VERSION 5.7 ;
  NOWIREEXTENSIONATPIN ON ;
  DIVIDERCHAR "/" ;
  BUSBITCHARS "[]" ;
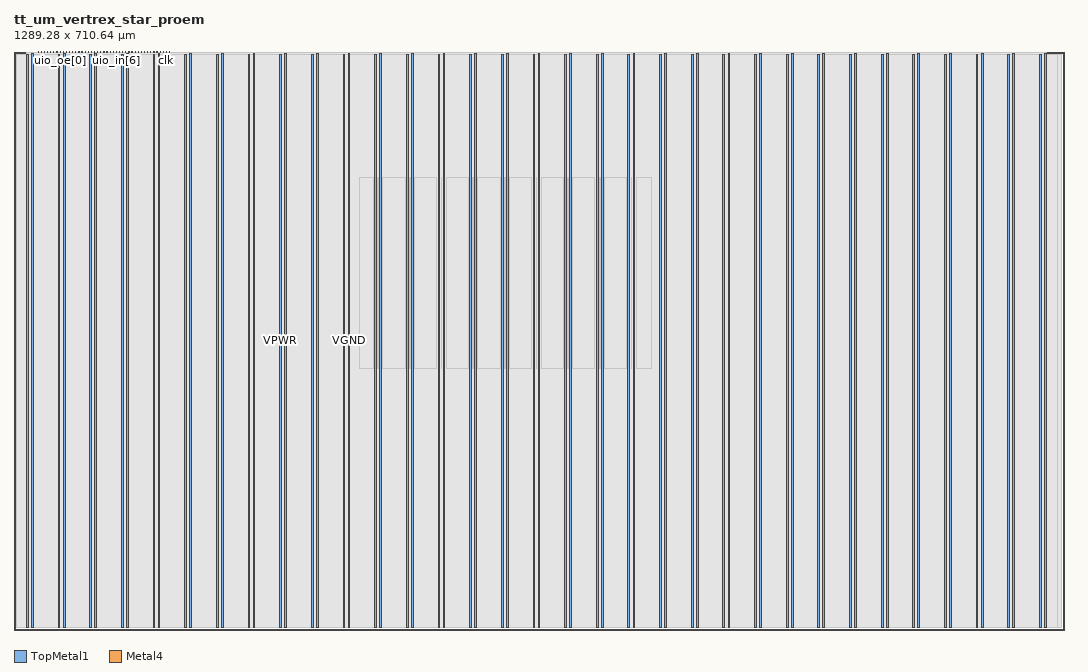
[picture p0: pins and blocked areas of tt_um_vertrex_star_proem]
MACRO tt_um_vertrex_star_proem
  CLASS BLOCK ;
  FOREIGN tt_um_vertrex_star_proem ;
  ORIGIN 0.000 0.000 ;
  SIZE 1289.280 BY 710.640 ;
  PIN VGND
    DIRECTION INOUT ;
    USE GROUND ;
    PORT
      LAYER TopMetal1 ;
        RECT 21.580 3.150 23.780 707.490 ;
    END
    PORT
      LAYER TopMetal1 ;
        RECT 60.450 3.150 62.650 707.490 ;
    END
    PORT
      LAYER TopMetal1 ;
        RECT 99.320 3.150 101.520 707.490 ;
    END
    PORT
      LAYER TopMetal1 ;
        RECT 138.190 3.150 140.390 707.490 ;
    END
    PORT
      LAYER TopMetal1 ;
        RECT 177.060 3.150 179.260 707.490 ;
    END
    PORT
      LAYER TopMetal1 ;
        RECT 215.930 3.150 218.130 707.490 ;
    END
    PORT
      LAYER TopMetal1 ;
        RECT 254.800 3.150 257.000 707.490 ;
    END
    PORT
      LAYER TopMetal1 ;
        RECT 293.670 3.150 295.870 707.490 ;
    END
    PORT
      LAYER TopMetal1 ;
        RECT 332.540 3.150 334.740 707.490 ;
    END
    PORT
      LAYER TopMetal1 ;
        RECT 371.410 3.150 373.610 707.490 ;
    END
    PORT
      LAYER TopMetal1 ;
        RECT 410.280 3.150 412.480 707.490 ;
    END
    PORT
      LAYER TopMetal1 ;
        RECT 449.150 3.150 451.350 707.490 ;
    END
    PORT
      LAYER TopMetal1 ;
        RECT 488.020 3.150 490.220 707.490 ;
    END
    PORT
      LAYER TopMetal1 ;
        RECT 526.890 3.150 529.090 707.490 ;
    END
    PORT
      LAYER TopMetal1 ;
        RECT 565.760 3.150 567.960 707.490 ;
    END
    PORT
      LAYER TopMetal1 ;
        RECT 604.630 3.150 606.830 707.490 ;
    END
    PORT
      LAYER TopMetal1 ;
        RECT 643.500 3.150 645.700 707.490 ;
    END
    PORT
      LAYER TopMetal1 ;
        RECT 682.370 3.150 684.570 707.490 ;
    END
    PORT
      LAYER TopMetal1 ;
        RECT 721.240 3.150 723.440 707.490 ;
    END
    PORT
      LAYER TopMetal1 ;
        RECT 760.110 3.150 762.310 707.490 ;
    END
    PORT
      LAYER TopMetal1 ;
        RECT 798.980 3.150 801.180 707.490 ;
    END
    PORT
      LAYER TopMetal1 ;
        RECT 837.850 3.150 840.050 707.490 ;
    END
    PORT
      LAYER TopMetal1 ;
        RECT 876.720 3.150 878.920 707.490 ;
    END
    PORT
      LAYER TopMetal1 ;
        RECT 915.590 3.150 917.790 707.490 ;
    END
    PORT
      LAYER TopMetal1 ;
        RECT 954.460 3.150 956.660 707.490 ;
    END
    PORT
      LAYER TopMetal1 ;
        RECT 993.330 3.150 995.530 707.490 ;
    END
    PORT
      LAYER TopMetal1 ;
        RECT 1032.200 3.150 1034.400 707.490 ;
    END
    PORT
      LAYER TopMetal1 ;
        RECT 1071.070 3.150 1073.270 707.490 ;
    END
    PORT
      LAYER TopMetal1 ;
        RECT 1109.940 3.150 1112.140 707.490 ;
    END
    PORT
      LAYER TopMetal1 ;
        RECT 1148.810 3.150 1151.010 707.490 ;
    END
    PORT
      LAYER TopMetal1 ;
        RECT 1187.680 3.150 1189.880 707.490 ;
    END
    PORT
      LAYER TopMetal1 ;
        RECT 1226.550 3.150 1228.750 707.490 ;
    END
    PORT
      LAYER TopMetal1 ;
        RECT 1265.420 3.150 1267.620 707.490 ;
    END
  END VGND
  PIN VPWR
    DIRECTION INOUT ;
    USE POWER ;
    PORT
      LAYER TopMetal1 ;
        RECT 15.380 3.560 17.580 707.080 ;
    END
    PORT
      LAYER TopMetal1 ;
        RECT 54.250 3.560 56.450 707.080 ;
    END
    PORT
      LAYER TopMetal1 ;
        RECT 93.120 3.560 95.320 707.080 ;
    END
    PORT
      LAYER TopMetal1 ;
        RECT 131.990 3.560 134.190 707.080 ;
    END
    PORT
      LAYER TopMetal1 ;
        RECT 170.860 3.560 173.060 707.080 ;
    END
    PORT
      LAYER TopMetal1 ;
        RECT 209.730 3.560 211.930 707.080 ;
    END
    PORT
      LAYER TopMetal1 ;
        RECT 248.600 3.560 250.800 707.080 ;
    END
    PORT
      LAYER TopMetal1 ;
        RECT 287.470 3.560 289.670 707.080 ;
    END
    PORT
      LAYER TopMetal1 ;
        RECT 326.340 3.560 328.540 707.080 ;
    END
    PORT
      LAYER TopMetal1 ;
        RECT 365.210 3.560 367.410 707.080 ;
    END
    PORT
      LAYER TopMetal1 ;
        RECT 404.080 3.560 406.280 707.080 ;
    END
    PORT
      LAYER TopMetal1 ;
        RECT 442.950 3.560 445.150 707.080 ;
    END
    PORT
      LAYER TopMetal1 ;
        RECT 481.820 3.560 484.020 707.080 ;
    END
    PORT
      LAYER TopMetal1 ;
        RECT 520.690 3.560 522.890 707.080 ;
    END
    PORT
      LAYER TopMetal1 ;
        RECT 559.560 3.560 561.760 707.080 ;
    END
    PORT
      LAYER TopMetal1 ;
        RECT 598.430 3.560 600.630 707.080 ;
    END
    PORT
      LAYER TopMetal1 ;
        RECT 637.300 3.560 639.500 707.080 ;
    END
    PORT
      LAYER TopMetal1 ;
        RECT 676.170 3.560 678.370 707.080 ;
    END
    PORT
      LAYER TopMetal1 ;
        RECT 715.040 3.560 717.240 707.080 ;
    END
    PORT
      LAYER TopMetal1 ;
        RECT 753.910 3.560 756.110 707.080 ;
    END
    PORT
      LAYER TopMetal1 ;
        RECT 792.780 3.560 794.980 707.080 ;
    END
    PORT
      LAYER TopMetal1 ;
        RECT 831.650 3.560 833.850 707.080 ;
    END
    PORT
      LAYER TopMetal1 ;
        RECT 870.520 3.560 872.720 707.080 ;
    END
    PORT
      LAYER TopMetal1 ;
        RECT 909.390 3.560 911.590 707.080 ;
    END
    PORT
      LAYER TopMetal1 ;
        RECT 948.260 3.560 950.460 707.080 ;
    END
    PORT
      LAYER TopMetal1 ;
        RECT 987.130 3.560 989.330 707.080 ;
    END
    PORT
      LAYER TopMetal1 ;
        RECT 1026.000 3.560 1028.200 707.080 ;
    END
    PORT
      LAYER TopMetal1 ;
        RECT 1064.870 3.560 1067.070 707.080 ;
    END
    PORT
      LAYER TopMetal1 ;
        RECT 1103.740 3.560 1105.940 707.080 ;
    END
    PORT
      LAYER TopMetal1 ;
        RECT 1142.610 3.560 1144.810 707.080 ;
    END
    PORT
      LAYER TopMetal1 ;
        RECT 1181.480 3.560 1183.680 707.080 ;
    END
    PORT
      LAYER TopMetal1 ;
        RECT 1220.350 3.560 1222.550 707.080 ;
    END
    PORT
      LAYER TopMetal1 ;
        RECT 1259.220 3.560 1261.420 707.080 ;
    END
  END VPWR
  PIN clk
    DIRECTION INPUT ;
    USE SIGNAL ;
    ANTENNAGATEAREA 1.450800 ;
    PORT
      LAYER Metal4 ;
        RECT 187.050 709.640 187.350 710.640 ;
    END
  END clk
  PIN ena
    DIRECTION INPUT ;
    USE SIGNAL ;
    PORT
      LAYER Metal4 ;
        RECT 190.890 709.640 191.190 710.640 ;
    END
  END ena
  PIN rst_n
    DIRECTION INPUT ;
    USE SIGNAL ;
    ANTENNAGATEAREA 0.180700 ;
    PORT
      LAYER Metal4 ;
        RECT 183.210 709.640 183.510 710.640 ;
    END
  END rst_n
  PIN ui_in[0]
    DIRECTION INPUT ;
    USE SIGNAL ;
    ANTENNAGATEAREA 0.180700 ;
    PORT
      LAYER Metal4 ;
        RECT 179.370 709.640 179.670 710.640 ;
    END
  END ui_in[0]
  PIN ui_in[1]
    DIRECTION INPUT ;
    USE SIGNAL ;
    PORT
      LAYER Metal4 ;
        RECT 175.530 709.640 175.830 710.640 ;
    END
  END ui_in[1]
  PIN ui_in[2]
    DIRECTION INPUT ;
    USE SIGNAL ;
    PORT
      LAYER Metal4 ;
        RECT 171.690 709.640 171.990 710.640 ;
    END
  END ui_in[2]
  PIN ui_in[3]
    DIRECTION INPUT ;
    USE SIGNAL ;
    PORT
      LAYER Metal4 ;
        RECT 167.850 709.640 168.150 710.640 ;
    END
  END ui_in[3]
  PIN ui_in[4]
    DIRECTION INPUT ;
    USE SIGNAL ;
    PORT
      LAYER Metal4 ;
        RECT 164.010 709.640 164.310 710.640 ;
    END
  END ui_in[4]
  PIN ui_in[5]
    DIRECTION INPUT ;
    USE SIGNAL ;
    PORT
      LAYER Metal4 ;
        RECT 160.170 709.640 160.470 710.640 ;
    END
  END ui_in[5]
  PIN ui_in[6]
    DIRECTION INPUT ;
    USE SIGNAL ;
    PORT
      LAYER Metal4 ;
        RECT 156.330 709.640 156.630 710.640 ;
    END
  END ui_in[6]
  PIN ui_in[7]
    DIRECTION INPUT ;
    USE SIGNAL ;
    PORT
      LAYER Metal4 ;
        RECT 152.490 709.640 152.790 710.640 ;
    END
  END ui_in[7]
  PIN uio_in[0]
    DIRECTION INPUT ;
    USE SIGNAL ;
    ANTENNAGATEAREA 0.180700 ;
    PORT
      LAYER Metal4 ;
        RECT 148.650 709.640 148.950 710.640 ;
    END
  END uio_in[0]
  PIN uio_in[1]
    DIRECTION INPUT ;
    USE SIGNAL ;
    ANTENNAGATEAREA 0.180700 ;
    PORT
      LAYER Metal4 ;
        RECT 144.810 709.640 145.110 710.640 ;
    END
  END uio_in[1]
  PIN uio_in[2]
    DIRECTION INPUT ;
    USE SIGNAL ;
    ANTENNAGATEAREA 0.180700 ;
    PORT
      LAYER Metal4 ;
        RECT 140.970 709.640 141.270 710.640 ;
    END
  END uio_in[2]
  PIN uio_in[3]
    DIRECTION INPUT ;
    USE SIGNAL ;
    ANTENNAGATEAREA 0.180700 ;
    PORT
      LAYER Metal4 ;
        RECT 137.130 709.640 137.430 710.640 ;
    END
  END uio_in[3]
  PIN uio_in[4]
    DIRECTION INPUT ;
    USE SIGNAL ;
    ANTENNAGATEAREA 0.180700 ;
    PORT
      LAYER Metal4 ;
        RECT 133.290 709.640 133.590 710.640 ;
    END
  END uio_in[4]
  PIN uio_in[5]
    DIRECTION INPUT ;
    USE SIGNAL ;
    ANTENNAGATEAREA 0.180700 ;
    PORT
      LAYER Metal4 ;
        RECT 129.450 709.640 129.750 710.640 ;
    END
  END uio_in[5]
  PIN uio_in[6]
    DIRECTION INPUT ;
    USE SIGNAL ;
    ANTENNAGATEAREA 0.180700 ;
    PORT
      LAYER Metal4 ;
        RECT 125.610 709.640 125.910 710.640 ;
    END
  END uio_in[6]
  PIN uio_in[7]
    DIRECTION INPUT ;
    USE SIGNAL ;
    ANTENNAGATEAREA 0.180700 ;
    PORT
      LAYER Metal4 ;
        RECT 121.770 709.640 122.070 710.640 ;
    END
  END uio_in[7]
  PIN uio_oe[0]
    DIRECTION OUTPUT ;
    USE SIGNAL ;
    ANTENNADIFFAREA 0.708600 ;
    PORT
      LAYER Metal4 ;
        RECT 56.490 709.640 56.790 710.640 ;
    END
  END uio_oe[0]
  PIN uio_oe[1]
    DIRECTION OUTPUT ;
    USE SIGNAL ;
    ANTENNADIFFAREA 0.708600 ;
    PORT
      LAYER Metal4 ;
        RECT 52.650 709.640 52.950 710.640 ;
    END
  END uio_oe[1]
  PIN uio_oe[2]
    DIRECTION OUTPUT ;
    USE SIGNAL ;
    ANTENNADIFFAREA 0.708600 ;
    PORT
      LAYER Metal4 ;
        RECT 48.810 709.640 49.110 710.640 ;
    END
  END uio_oe[2]
  PIN uio_oe[3]
    DIRECTION OUTPUT ;
    USE SIGNAL ;
    ANTENNADIFFAREA 0.708600 ;
    PORT
      LAYER Metal4 ;
        RECT 44.970 709.640 45.270 710.640 ;
    END
  END uio_oe[3]
  PIN uio_oe[4]
    DIRECTION OUTPUT ;
    USE SIGNAL ;
    ANTENNADIFFAREA 0.708600 ;
    PORT
      LAYER Metal4 ;
        RECT 41.130 709.640 41.430 710.640 ;
    END
  END uio_oe[4]
  PIN uio_oe[5]
    DIRECTION OUTPUT ;
    USE SIGNAL ;
    ANTENNADIFFAREA 0.708600 ;
    PORT
      LAYER Metal4 ;
        RECT 37.290 709.640 37.590 710.640 ;
    END
  END uio_oe[5]
  PIN uio_oe[6]
    DIRECTION OUTPUT ;
    USE SIGNAL ;
    ANTENNADIFFAREA 0.299200 ;
    PORT
      LAYER Metal4 ;
        RECT 33.450 709.640 33.750 710.640 ;
    END
  END uio_oe[6]
  PIN uio_oe[7]
    DIRECTION OUTPUT ;
    USE SIGNAL ;
    ANTENNADIFFAREA 0.299200 ;
    PORT
      LAYER Metal4 ;
        RECT 29.610 709.640 29.910 710.640 ;
    END
  END uio_oe[7]
  PIN uio_out[0]
    DIRECTION OUTPUT ;
    USE SIGNAL ;
    ANTENNADIFFAREA 0.708600 ;
    PORT
      LAYER Metal4 ;
        RECT 87.210 709.640 87.510 710.640 ;
    END
  END uio_out[0]
  PIN uio_out[1]
    DIRECTION OUTPUT ;
    USE SIGNAL ;
    ANTENNADIFFAREA 0.708600 ;
    PORT
      LAYER Metal4 ;
        RECT 83.370 709.640 83.670 710.640 ;
    END
  END uio_out[1]
  PIN uio_out[2]
    DIRECTION OUTPUT ;
    USE SIGNAL ;
    ANTENNADIFFAREA 0.708600 ;
    PORT
      LAYER Metal4 ;
        RECT 79.530 709.640 79.830 710.640 ;
    END
  END uio_out[2]
  PIN uio_out[3]
    DIRECTION OUTPUT ;
    USE SIGNAL ;
    ANTENNADIFFAREA 0.708600 ;
    PORT
      LAYER Metal4 ;
        RECT 75.690 709.640 75.990 710.640 ;
    END
  END uio_out[3]
  PIN uio_out[4]
    DIRECTION OUTPUT ;
    USE SIGNAL ;
    ANTENNADIFFAREA 0.708600 ;
    PORT
      LAYER Metal4 ;
        RECT 71.850 709.640 72.150 710.640 ;
    END
  END uio_out[4]
  PIN uio_out[5]
    DIRECTION OUTPUT ;
    USE SIGNAL ;
    ANTENNADIFFAREA 0.708600 ;
    PORT
      LAYER Metal4 ;
        RECT 68.010 709.640 68.310 710.640 ;
    END
  END uio_out[5]
  PIN uio_out[6]
    DIRECTION OUTPUT ;
    USE SIGNAL ;
    ANTENNADIFFAREA 0.299200 ;
    PORT
      LAYER Metal4 ;
        RECT 64.170 709.640 64.470 710.640 ;
    END
  END uio_out[6]
  PIN uio_out[7]
    DIRECTION OUTPUT ;
    USE SIGNAL ;
    ANTENNADIFFAREA 0.299200 ;
    PORT
      LAYER Metal4 ;
        RECT 60.330 709.640 60.630 710.640 ;
    END
  END uio_out[7]
  PIN uo_out[0]
    DIRECTION OUTPUT ;
    USE SIGNAL ;
    ANTENNADIFFAREA 0.708600 ;
    PORT
      LAYER Metal4 ;
        RECT 117.930 709.640 118.230 710.640 ;
    END
  END uo_out[0]
  PIN uo_out[1]
    DIRECTION OUTPUT ;
    USE SIGNAL ;
    ANTENNADIFFAREA 0.708600 ;
    PORT
      LAYER Metal4 ;
        RECT 114.090 709.640 114.390 710.640 ;
    END
  END uo_out[1]
  PIN uo_out[2]
    DIRECTION OUTPUT ;
    USE SIGNAL ;
    ANTENNADIFFAREA 0.708600 ;
    PORT
      LAYER Metal4 ;
        RECT 110.250 709.640 110.550 710.640 ;
    END
  END uo_out[2]
  PIN uo_out[3]
    DIRECTION OUTPUT ;
    USE SIGNAL ;
    ANTENNADIFFAREA 0.708600 ;
    PORT
      LAYER Metal4 ;
        RECT 106.410 709.640 106.710 710.640 ;
    END
  END uo_out[3]
  PIN uo_out[4]
    DIRECTION OUTPUT ;
    USE SIGNAL ;
    ANTENNADIFFAREA 0.708600 ;
    PORT
      LAYER Metal4 ;
        RECT 102.570 709.640 102.870 710.640 ;
    END
  END uo_out[4]
  PIN uo_out[5]
    DIRECTION OUTPUT ;
    USE SIGNAL ;
    ANTENNADIFFAREA 0.708600 ;
    PORT
      LAYER Metal4 ;
        RECT 98.730 709.640 99.030 710.640 ;
    END
  END uo_out[5]
  PIN uo_out[6]
    DIRECTION OUTPUT ;
    USE SIGNAL ;
    ANTENNADIFFAREA 0.708600 ;
    PORT
      LAYER Metal4 ;
        RECT 94.890 709.640 95.190 710.640 ;
    END
  END uo_out[6]
  PIN uo_out[7]
    DIRECTION OUTPUT ;
    USE SIGNAL ;
    ANTENNADIFFAREA 0.708600 ;
    PORT
      LAYER Metal4 ;
        RECT 91.050 709.640 91.350 710.640 ;
    END
  END uo_out[7]
  OBS
      LAYER GatPoly ;
        RECT 2.880 3.630 1286.400 707.010 ;
      LAYER Metal1 ;
        RECT 2.880 3.560 1286.400 707.080 ;
      LAYER Metal2 ;
        RECT 3.255 3.635 1281.705 707.005 ;
      LAYER Metal3 ;
        RECT 3.215 3.680 1281.745 706.960 ;
      LAYER Metal4 ;
        RECT 15.560 709.430 29.400 709.640 ;
        RECT 30.120 709.430 33.240 709.640 ;
        RECT 33.960 709.430 37.080 709.640 ;
        RECT 37.800 709.430 40.920 709.640 ;
        RECT 41.640 709.430 44.760 709.640 ;
        RECT 45.480 709.430 48.600 709.640 ;
        RECT 49.320 709.430 52.440 709.640 ;
        RECT 53.160 709.430 56.280 709.640 ;
        RECT 57.000 709.430 60.120 709.640 ;
        RECT 60.840 709.430 63.960 709.640 ;
        RECT 64.680 709.430 67.800 709.640 ;
        RECT 68.520 709.430 71.640 709.640 ;
        RECT 72.360 709.430 75.480 709.640 ;
        RECT 76.200 709.430 79.320 709.640 ;
        RECT 80.040 709.430 83.160 709.640 ;
        RECT 83.880 709.430 87.000 709.640 ;
        RECT 87.720 709.430 90.840 709.640 ;
        RECT 91.560 709.430 94.680 709.640 ;
        RECT 95.400 709.430 98.520 709.640 ;
        RECT 99.240 709.430 102.360 709.640 ;
        RECT 103.080 709.430 106.200 709.640 ;
        RECT 106.920 709.430 110.040 709.640 ;
        RECT 110.760 709.430 113.880 709.640 ;
        RECT 114.600 709.430 117.720 709.640 ;
        RECT 118.440 709.430 121.560 709.640 ;
        RECT 122.280 709.430 125.400 709.640 ;
        RECT 126.120 709.430 129.240 709.640 ;
        RECT 129.960 709.430 133.080 709.640 ;
        RECT 133.800 709.430 136.920 709.640 ;
        RECT 137.640 709.430 140.760 709.640 ;
        RECT 141.480 709.430 144.600 709.640 ;
        RECT 145.320 709.430 148.440 709.640 ;
        RECT 149.160 709.430 152.280 709.640 ;
        RECT 153.000 709.430 156.120 709.640 ;
        RECT 156.840 709.430 159.960 709.640 ;
        RECT 160.680 709.430 163.800 709.640 ;
        RECT 164.520 709.430 167.640 709.640 ;
        RECT 168.360 709.430 171.480 709.640 ;
        RECT 172.200 709.430 175.320 709.640 ;
        RECT 176.040 709.430 179.160 709.640 ;
        RECT 179.880 709.430 183.000 709.640 ;
        RECT 183.720 709.430 186.840 709.640 ;
        RECT 187.560 709.430 190.680 709.640 ;
        RECT 191.400 709.430 1267.440 709.640 ;
        RECT 15.560 3.635 1267.440 709.430 ;
      LAYER Metal5 ;
        RECT 15.515 3.470 1267.485 707.170 ;
      LAYER TopMetal1 ;
        RECT 423.940 320.480 441.310 555.220 ;
        RECT 446.790 320.480 447.510 555.220 ;
        RECT 452.990 320.480 480.180 555.220 ;
        RECT 485.660 320.480 486.380 555.220 ;
        RECT 491.860 320.480 519.050 555.220 ;
        RECT 524.530 320.480 525.250 555.220 ;
        RECT 530.730 320.480 557.920 555.220 ;
        RECT 563.400 320.480 564.120 555.220 ;
        RECT 569.600 320.480 596.790 555.220 ;
        RECT 602.270 320.480 602.990 555.220 ;
        RECT 608.470 320.480 635.660 555.220 ;
        RECT 641.140 320.480 641.860 555.220 ;
        RECT 647.340 320.480 674.530 555.220 ;
        RECT 680.010 320.480 680.730 555.220 ;
        RECT 686.210 320.480 713.400 555.220 ;
        RECT 718.880 320.480 719.600 555.220 ;
        RECT 725.080 320.480 752.270 555.220 ;
        RECT 757.750 320.480 758.470 555.220 ;
        RECT 763.950 320.480 783.100 555.220 ;
  END
END tt_um_vertrex_star_proem
END LIBRARY

